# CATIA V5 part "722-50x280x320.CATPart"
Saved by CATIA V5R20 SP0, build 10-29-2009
Part number: 722-50x280x320
Definition: NONE
Nomenclature: 722-50x280x320
Source: Unknown
Description: 722-50x280x320
Bounding box of the stored display mesh (mm): x -25 to 25, y -25 to 25, z -262 to 58
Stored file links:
  C:\Users\Utente\Desktop\IO LAVORO\3D X SITO CF\X SITO\722\722-50x280x320.CATPart

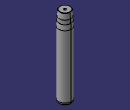
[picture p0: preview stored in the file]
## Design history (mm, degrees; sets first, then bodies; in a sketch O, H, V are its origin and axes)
Body1 "722-50x280x320" (main body)
  Solid1: solid without history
